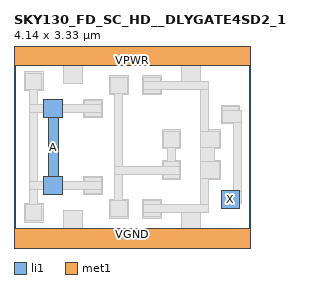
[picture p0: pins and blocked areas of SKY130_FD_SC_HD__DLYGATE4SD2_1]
MACRO SKY130_FD_SC_HD__DLYGATE4SD2_1
 CLASS CORE ;
 FOREIGN SKY130_FD_SC_HD__DLYGATE4SD2_1 0 0 ;
 SIZE 4.14 BY 3.33 ;
 ORIGIN 0 0 ;
 SYMMETRY X Y R90 ;
 SITE unit ;
  PIN VPWR
   DIRECTION INOUT ;
   USE POWER ;
   SHAPE ABUTMENT ;
    PORT
     CLASS CORE ;
       LAYER li1 ;
        RECT 0.00000000 3.09000000 4.14000000 3.57000000 ;
       LAYER met1 ;
        RECT 0.00000000 3.09000000 4.14000000 3.57000000 ;
    END
  END VPWR

  PIN VGND
   DIRECTION INOUT ;
   USE POWER ;
   SHAPE ABUTMENT ;
    PORT
     CLASS CORE ;
       LAYER li1 ;
        RECT 0.00000000 -0.24000000 4.14000000 0.24000000 ;
       LAYER met1 ;
        RECT 0.00000000 -0.24000000 4.14000000 0.24000000 ;
    END
  END VGND

  PIN X
   DIRECTION INOUT ;
   USE SIGNAL ;
   SHAPE ABUTMENT ;
    PORT
     CLASS CORE ;
       LAYER li1 ;
        RECT 3.63000000 0.58000000 3.96000000 0.91000000 ;
    END
  END X

  PIN A
   DIRECTION INOUT ;
   USE SIGNAL ;
   SHAPE ABUTMENT ;
    PORT
     CLASS CORE ;
       LAYER li1 ;
        RECT 0.52500000 0.82500000 0.85500000 1.15500000 ;
        RECT 0.60500000 1.15500000 0.77500000 2.17500000 ;
        RECT 0.52500000 2.17500000 0.85500000 2.50500000 ;
    END
  END A

 OBS
    LAYER polycont ;
     RECT 1.29500000 0.90500000 1.46500000 1.07500000 ;
     RECT 1.29500000 2.25500000 1.46500000 2.42500000 ;
     RECT 0.60500000 0.90500000 0.77500000 1.07500000 ;
     RECT 0.60500000 2.25500000 0.77500000 2.42500000 ;
     RECT 3.36500000 1.17500000 3.53500000 1.34500000 ;
     RECT 3.36500000 1.71500000 3.53500000 1.88500000 ;
     RECT 2.67500000 1.17500000 2.84500000 1.34500000 ;
     RECT 2.67500000 1.71500000 2.84500000 1.88500000 ;

    LAYER pdiffc ;
     RECT 0.95000000 2.86000000 1.12000000 3.03000000 ;
     RECT 3.02000000 2.86000000 3.19000000 3.03000000 ;
     RECT 0.26000000 2.73000000 0.43000000 2.90000000 ;
     RECT 2.33000000 2.66000000 2.50000000 2.83000000 ;
     RECT 3.71000000 2.15000000 3.88000000 2.32000000 ;
     RECT 1.75500000 2.66000000 1.92500000 2.83000000 ;

    LAYER ndiffc ;
     RECT 0.95000000 0.30000000 1.12000000 0.47000000 ;
     RECT 3.02000000 0.30000000 3.19000000 0.47000000 ;
     RECT 0.26000000 0.43000000 0.43000000 0.60000000 ;
     RECT 2.33000000 0.50000000 2.50000000 0.67000000 ;
     RECT 3.71000000 0.66000000 3.88000000 0.83000000 ;
     RECT 1.75500000 0.50000000 1.92500000 0.67000000 ;

    LAYER li1 ;
     RECT 0.87000000 2.78000000 1.20000000 3.09000000 ;
     RECT 2.94000000 2.78000000 3.27000000 3.09000000 ;
     RECT 0.00000000 3.09000000 4.14000000 3.57000000 ;
     RECT 0.00000000 -0.24000000 4.14000000 0.24000000 ;
     RECT 0.87000000 0.24000000 1.20000000 0.55000000 ;
     RECT 2.94000000 0.24000000 3.27000000 0.55000000 ;
     RECT 0.18000000 0.35000000 0.51000000 0.68000000 ;
     RECT 1.21500000 0.82500000 1.54500000 1.15500000 ;
     RECT 1.21500000 2.17500000 1.54500000 2.50500000 ;
     RECT 0.18000000 2.65000000 0.51000000 2.98000000 ;
     RECT 0.52500000 0.82500000 0.85500000 1.15500000 ;
     RECT 0.60500000 1.15500000 0.77500000 2.17500000 ;
     RECT 0.52500000 2.17500000 0.85500000 2.50500000 ;
     RECT 2.25000000 0.42000000 2.58000000 0.75000000 ;
     RECT 3.28500000 1.09500000 3.61500000 1.42500000 ;
     RECT 3.28500000 1.63500000 3.61500000 1.96500000 ;
     RECT 2.25000000 2.58000000 2.58000000 2.91000000 ;
     RECT 3.63000000 0.58000000 3.96000000 0.91000000 ;
     RECT 3.63000000 2.07000000 3.96000000 2.40000000 ;
     RECT 1.67500000 0.42000000 2.00500000 0.75000000 ;
     RECT 2.59500000 1.09500000 2.92500000 1.42500000 ;
     RECT 2.59500000 1.63500000 2.92500000 1.96500000 ;
     RECT 1.67500000 2.58000000 2.00500000 2.91000000 ;

    LAYER viali ;
     RECT 3.02000000 3.24500000 3.19000000 3.41500000 ;
     RECT 3.02000000 -0.08500000 3.19000000 0.08500000 ;
     RECT 0.26000000 0.43000000 0.43000000 0.60000000 ;
     RECT 1.29500000 0.90500000 1.46500000 1.07500000 ;
     RECT 1.29500000 2.25500000 1.46500000 2.42500000 ;
     RECT 0.26000000 2.73000000 0.43000000 2.90000000 ;
     RECT 2.33000000 0.50000000 2.50000000 0.67000000 ;
     RECT 3.36500000 1.17500000 3.53500000 1.34500000 ;
     RECT 3.36500000 1.71500000 3.53500000 1.88500000 ;
     RECT 2.33000000 2.66000000 2.50000000 2.83000000 ;
     RECT 3.71000000 0.66000000 3.88000000 0.83000000 ;
     RECT 3.71000000 2.15000000 3.88000000 2.32000000 ;
     RECT 1.75500000 0.50000000 1.92500000 0.67000000 ;
     RECT 2.67500000 1.17500000 2.84500000 1.34500000 ;
     RECT 2.67500000 1.71500000 2.84500000 1.88500000 ;
     RECT 1.75500000 2.66000000 1.92500000 2.83000000 ;

    LAYER met1 ;
     RECT 0.00000000 3.09000000 4.14000000 3.57000000 ;
     RECT 0.00000000 -0.24000000 4.14000000 0.24000000 ;
     RECT 0.20000000 0.37000000 0.49000000 0.66000000 ;
     RECT 0.27500000 0.66000000 0.41500000 0.92000000 ;
     RECT 1.23500000 0.84500000 1.52500000 0.92000000 ;
     RECT 0.27500000 0.92000000 1.52500000 1.06000000 ;
     RECT 1.23500000 1.06000000 1.52500000 1.13500000 ;
     RECT 0.27500000 1.06000000 0.41500000 2.27000000 ;
     RECT 1.23500000 2.19500000 1.52500000 2.27000000 ;
     RECT 0.27500000 2.27000000 1.52500000 2.41000000 ;
     RECT 1.23500000 2.41000000 1.52500000 2.48500000 ;
     RECT 0.27500000 2.41000000 0.41500000 2.67000000 ;
     RECT 0.20000000 2.67000000 0.49000000 2.96000000 ;
     RECT 2.27000000 0.44000000 2.56000000 0.51500000 ;
     RECT 2.27000000 0.51500000 3.40500000 0.65500000 ;
     RECT 2.27000000 0.65500000 2.56000000 0.73000000 ;
     RECT 3.26500000 0.65500000 3.40500000 1.11500000 ;
     RECT 3.26500000 1.11500000 3.59500000 1.40500000 ;
     RECT 3.26500000 1.40500000 3.52000000 1.65500000 ;
     RECT 3.26500000 1.65500000 3.59500000 1.94500000 ;
     RECT 2.27000000 2.60000000 2.56000000 2.67500000 ;
     RECT 3.26500000 1.94500000 3.40500000 2.67500000 ;
     RECT 2.27000000 2.67500000 3.40500000 2.81500000 ;
     RECT 2.27000000 2.81500000 2.56000000 2.89000000 ;
     RECT 3.65000000 0.60000000 3.94000000 0.67500000 ;
     RECT 3.65000000 0.67500000 3.98000000 0.89000000 ;
     RECT 3.84000000 0.89000000 3.98000000 2.09000000 ;
     RECT 3.65000000 2.09000000 3.98000000 2.30500000 ;
     RECT 3.65000000 2.30500000 3.94000000 2.38000000 ;
     RECT 1.69500000 0.44000000 1.98500000 0.73000000 ;
     RECT 1.77000000 0.73000000 1.91000000 1.19000000 ;
     RECT 2.61500000 1.11500000 2.90500000 1.19000000 ;
     RECT 1.77000000 1.19000000 2.90500000 1.33000000 ;
     RECT 2.61500000 1.33000000 2.90500000 1.40500000 ;
     RECT 2.69000000 1.40500000 2.83000000 1.65500000 ;
     RECT 2.61500000 1.65500000 2.90500000 1.94500000 ;
     RECT 1.77000000 1.33000000 1.91000000 2.60000000 ;
     RECT 1.69500000 2.60000000 1.98500000 2.89000000 ;

    LAYER via ;


    LAYER met2 ;


    LAYER via2 ;


    LAYER met3 ;


 END
END SKY130_FD_SC_HD__DLYGATE4SD2_1
